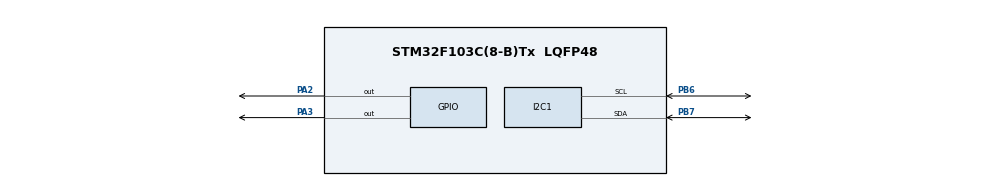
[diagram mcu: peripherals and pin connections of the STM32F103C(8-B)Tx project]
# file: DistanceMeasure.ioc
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I2C1.I2C_Mode=I2C_Fast
Mcu.Family=STM32F1
Mcu.Name=STM32F103C(8-B)Tx
Mcu.Package=LQFP48
NVIC.PriorityGroup=NVIC_PRIORITYGROUP_4
PA2.Signal=GPIO_Output
PA3.Signal=GPIO_Output
PB6.Mode=I2C
PB6.Signal=I2C1_SCL
PB7.Mode=I2C
PB7.Signal=I2C1_SDA
PD0-OSC_IN.Mode=HSE-External-Oscillator
PD0-OSC_IN.Signal=RCC_OSC_IN
PD1-OSC_OUT.Mode=HSE-External-Oscillator
PD1-OSC_OUT.Signal=RCC_OSC_OUT
ProjectManager.HeapSize=0x200
ProjectManager.StackSize=0x400
ProjectManager.TargetToolchain=STM32CubeIDE
RCC.APB1Freq_Value=8000000
RCC.APB2Freq_Value=8000000
TIM1.Prescaler=71
VP_SYS_VS_ND.Mode=No_Debug
VP_TIM1_VS_ClockSourceINT.Mode=Internal
board=custom

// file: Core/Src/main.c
/* USER CODE BEGIN Header */
/**
  ******************************************************************************
  * @file           : main.c
  * @brief          : Main program body
  ******************************************************************************
  * @attention
  *
  * Copyright (c) 2022 STMicroelectronics.
  * All rights reserved.
  *
  * This software is licensed under terms that can be found in the LICENSE file
  * in the root directory of this software component.
  * If no LICENSE file comes with this software, it is provided AS-IS.
  *
  ******************************************************************************
  */
/* USER CODE END Header */
#include "main.h"

/* USER CODE BEGIN Includes */
#include "liquidcrystal_i2c.h"
#include "stdio.h"
/* USER CODE END Includes */

 I2C_HandleTypeDef hi2c1;

TIM_HandleTypeDef htim1;

/* USER CODE BEGIN PV */
#define TRIG_PIN GPIO_PIN_3
#define TRIG_PORT GPIOA
#define ECHO_PIN GPIO_PIN_2
#define ECHO_PORT GPIOA
uint32_t pMillis;
uint32_t Value1 = 0;
uint32_t Value2 = 0;
uint16_t Distance  = 0;  // cm
char strCopy[15];
/* USER CODE END PV */

void SystemClock_Config(void);
static void MX_GPIO_Init(void);
static void MX_I2C1_Init(void);
static void MX_TIM1_Init(void);

int main(void)
{
  /* USER CODE BEGIN 1 */
	char Temp;
  /* USER CODE END 1 */

  /* MCU Configuration--------------------------------------------------------*/

  /* Reset of all peripherals, Initializes the Flash interface and the Systick. */
  HAL_Init();

  /* USER CODE BEGIN Init */
  HD44780_Backlight();
  /* USER CODE END Init */

  /* Configure the system clock */
  SystemClock_Config();

  /* Initialize all configured peripherals */
  MX_GPIO_Init();
  MX_I2C1_Init();
  MX_TIM1_Init();
  /* USER CODE BEGIN 2 */
  HAL_TIM_Base_Start(&htim1);
  HAL_GPIO_WritePin(TRIG_PORT, TRIG_PIN, GPIO_PIN_RESET);  // pull the TRIG pin low
  HD44780_Init(2);
  HD44780_Clear();
  HD44780_SetCursor(0,0);
  HD44780_PrintStr("KHOANG CACH DO DUOC");
  /* USER CODE END 2 */

  /* Infinite loop */
  while (1)
  {
	  HAL_GPIO_WritePin(TRIG_PORT, TRIG_PIN, GPIO_PIN_SET);  // pull the TRIG pin HIGH
	  __HAL_TIM_SET_COUNTER(&htim1, 0);
	  while (__HAL_TIM_GET_COUNTER (&htim1) < 10);  // wait for 10 us
	  HAL_GPIO_WritePin(TRIG_PORT, TRIG_PIN, GPIO_PIN_RESET);  // pull the TRIG pin low

	  pMillis = HAL_GetTick(); // used this to avoid infinite while loop  (for timeout)
	  // wait for the echo pin to go high
	  while (!(HAL_GPIO_ReadPin (ECHO_PORT, ECHO_PIN)) && pMillis + 10 >  HAL_GetTick());
	  Value1 = __HAL_TIM_GET_COUNTER (&htim1);

	  pMillis = HAL_GetTick(); // used this to avoid infinite while loop (for timeout)
	  // wait for the echo pin to go low
	  while ((HAL_GPIO_ReadPin (ECHO_PORT, ECHO_PIN)) && pMillis + 50 > HAL_GetTick());
	  Value2 = __HAL_TIM_GET_COUNTER (&htim1);

	  Distance = (Value2-Value1)* 0.034/2;
	  itoa(Distance, Temp, 10);
	  HD44780_SetCursor(7,1);
	  HD44780_PrintStr(Temp);

  }
}

void SystemClock_Config(void)
{
  RCC_OscInitTypeDef RCC_OscInitStruct = {0};
  RCC_ClkInitTypeDef RCC_ClkInitStruct = {0};

  /** Initializes the RCC Oscillators according to the specified parameters
  * in the RCC_OscInitTypeDef structure.
  */
  RCC_OscInitStruct.OscillatorType = RCC_OSCILLATORTYPE_HSI;
  RCC_OscInitStruct.HSIState = RCC_HSI_ON;
  RCC_OscInitStruct.HSICalibrationValue = RCC_HSICALIBRATION_DEFAULT;
  RCC_OscInitStruct.PLL.PLLState = RCC_PLL_NONE;
  if (HAL_RCC_OscConfig(&RCC_OscInitStruct) != HAL_OK)
  {
    Error_Handler();
  }

  /** Initializes the CPU, AHB and APB buses clocks
  */
  RCC_ClkInitStruct.ClockType = RCC_CLOCKTYPE_HCLK|RCC_CLOCKTYPE_SYSCLK
                              |RCC_CLOCKTYPE_PCLK1|RCC_CLOCKTYPE_PCLK2;
  RCC_ClkInitStruct.SYSCLKSource = RCC_SYSCLKSOURCE_HSI;
  RCC_ClkInitStruct.AHBCLKDivider = RCC_SYSCLK_DIV1;
  RCC_ClkInitStruct.APB1CLKDivider = RCC_HCLK_DIV1;
  RCC_ClkInitStruct.APB2CLKDivider = RCC_HCLK_DIV1;

  if (HAL_RCC_ClockConfig(&RCC_ClkInitStruct, FLASH_LATENCY_0) != HAL_OK)
  {
    Error_Handler();
  }
}

static void MX_I2C1_Init(void)
{

  hi2c1.Instance = I2C1;
  hi2c1.Init.ClockSpeed = 400000;
  hi2c1.Init.DutyCycle = I2C_DUTYCYCLE_2;
  hi2c1.Init.OwnAddress1 = 0;
  hi2c1.Init.AddressingMode = I2C_ADDRESSINGMODE_7BIT;
  hi2c1.Init.DualAddressMode = I2C_DUALADDRESS_DISABLE;
  hi2c1.Init.OwnAddress2 = 0;
  hi2c1.Init.GeneralCallMode = I2C_GENERALCALL_DISABLE;
  hi2c1.Init.NoStretchMode = I2C_NOSTRETCH_DISABLE;
  if (HAL_I2C_Init(&hi2c1) != HAL_OK)
  {
    Error_Handler();
  }

}

static void MX_TIM1_Init(void)
{

  TIM_ClockConfigTypeDef sClockSourceConfig = {0};
  TIM_MasterConfigTypeDef sMasterConfig = {0};

  htim1.Instance = TIM1;
  htim1.Init.Prescaler = 71;
  htim1.Init.CounterMode = TIM_COUNTERMODE_UP;
  htim1.Init.Period = 65535;
  htim1.Init.ClockDivision = TIM_CLOCKDIVISION_DIV1;
  htim1.Init.RepetitionCounter = 0;
  htim1.Init.AutoReloadPreload = TIM_AUTORELOAD_PRELOAD_DISABLE;
  if (HAL_TIM_Base_Init(&htim1) != HAL_OK)
  {
    Error_Handler();
  }
  sClockSourceConfig.ClockSource = TIM_CLOCKSOURCE_INTERNAL;
  if (HAL_TIM_ConfigClockSource(&htim1, &sClockSourceConfig) != HAL_OK)
  {
    Error_Handler();
  }
  sMasterConfig.MasterOutputTrigger = TIM_TRGO_RESET;
  sMasterConfig.MasterSlaveMode = TIM_MASTERSLAVEMODE_DISABLE;
  if (HAL_TIMEx_MasterConfigSynchronization(&htim1, &sMasterConfig) != HAL_OK)
  {
    Error_Handler();
  }

}

static void MX_GPIO_Init(void)
{
  GPIO_InitTypeDef GPIO_InitStruct = {0};

  /* GPIO Ports Clock Enable */
  __HAL_RCC_GPIOD_CLK_ENABLE();
  __HAL_RCC_GPIOA_CLK_ENABLE();
  __HAL_RCC_GPIOB_CLK_ENABLE();

  /*Configure GPIO pin Output Level */
  HAL_GPIO_WritePin(GPIOA, GPIO_PIN_8, GPIO_PIN_RESET);

  /*Configure GPIO pin : PA8 */
  GPIO_InitStruct.Pin = GPIO_PIN_8;
  GPIO_InitStruct.Mode = GPIO_MODE_OUTPUT_PP;
  GPIO_InitStruct.Pull = GPIO_NOPULL;
  GPIO_InitStruct.Speed = GPIO_SPEED_FREQ_LOW;
  HAL_GPIO_Init(GPIOA, &GPIO_InitStruct);

  /*Configure GPIO pin : PA9 */
  GPIO_InitStruct.Pin = GPIO_PIN_9;
  GPIO_InitStruct.Mode = GPIO_MODE_INPUT;
  GPIO_InitStruct.Pull = GPIO_NOPULL;
  HAL_GPIO_Init(GPIOA, &GPIO_InitStruct);

}

void Error_Handler(void)
{
  __disable_irq();
  while (1)
  {
  }
}
